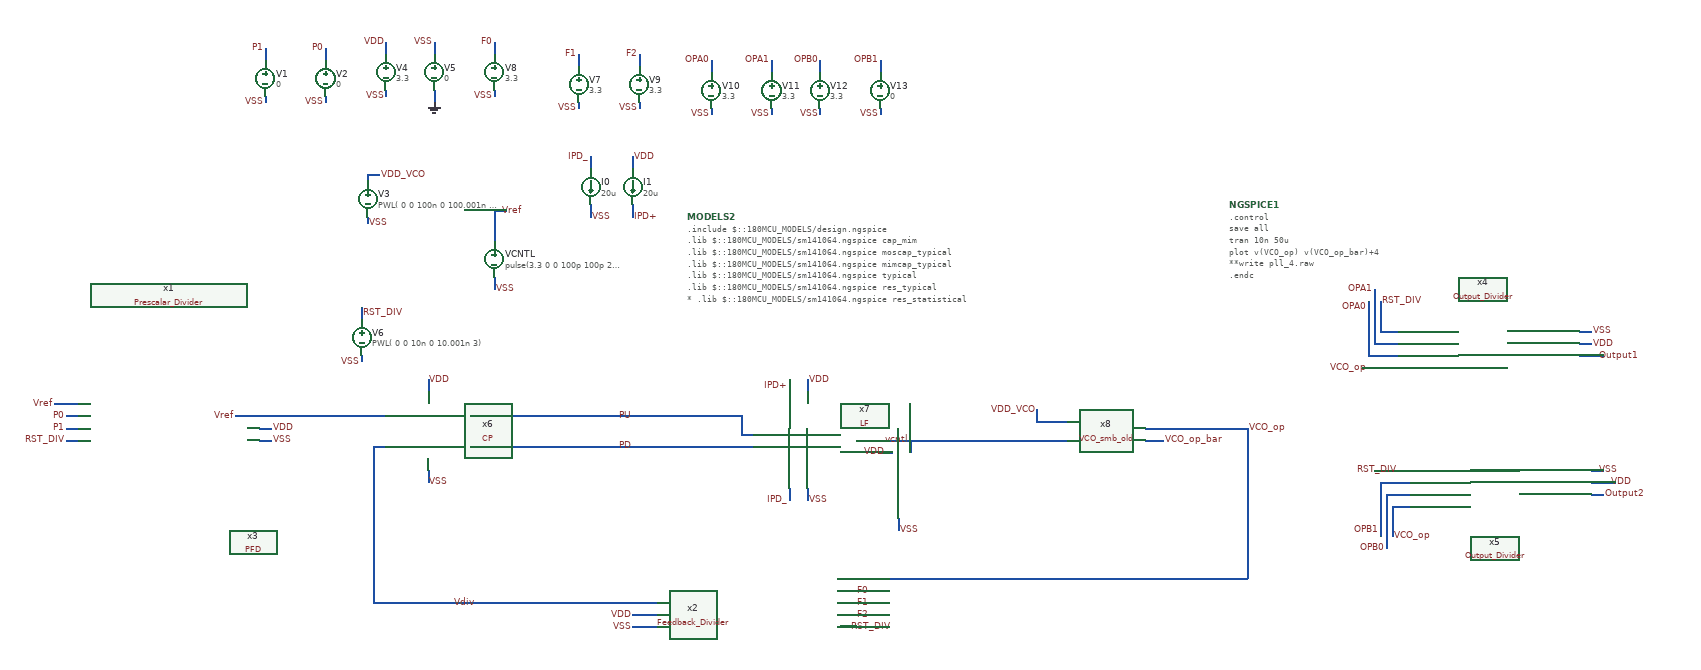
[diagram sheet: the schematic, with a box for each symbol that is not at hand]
v {xschem version=3.1.0 file_version=1.2
}
G {}
K {}
V {}
S {}
E {}
N 90 -2870 110 -2870 {
lab=P0}
N 90 -2850 110 -2850 {
lab=P1}
N 90 -2830 110 -2830 {
lab=RST_DIV}
N 410 -2830 430 -2830 {
lab=VSS}
N 410 -2850 430 -2850 {
lab=VDD}
N 420 -3400 420 -3390 {
lab=VSS}
N 420 -3480 420 -3460 {
lab=P1}
N 520 -3400 520 -3390 {
lab=VSS}
N 520 -3480 520 -3460 {
lab=P0}
N 690 -2930 690 -2910 {
lab=VDD}
N 690 -2780 690 -2760 {
lab=VSS}
N 600 -2870 620 -2870 {
lab=Vref}
N 600 -2820 620 -2820 {
lab=Vdiv}
N 760 -2820 780 -2820 {
lab=PD}
N 580 -2870 600 -2870 {
lab=Vref}
N 780 -2870 870 -2870 {
lab=PU}
N 780 -2820 870 -2820 {
lab=PD}
N 1060 -2870 1210 -2870 {
lab=PU}
N 1060 -2820 1210 -2820 {
lab=PD}
N 600 -2820 600 -2690 {
lab=Vdiv}
N 600 -2590 600 -2560 {
lab=Vdiv}
N 610 -2560 900 -2560 {
lab=Vdiv}
N 1990 -2850 2050 -2850 {
lab=VCO_op}
N 1930 -2850 1990 -2850 {
lab=VCO_op}
N 1880 -2850 1930 -2850 {
lab=VCO_op}
N 1700 -2860 1740 -2860 {
lab=VDD_VCO}
N 1880 -2830 1910 -2830 {
lab=VCO_op_bar}
N 600 -2690 600 -2590 {
lab=Vdiv}
N 600 -2560 610 -2560 {
lab=Vdiv}
N 760 -2870 780 -2870 {
lab=PU}
N 870 -2870 1060 -2870 {
lab=PU}
N 870 -2820 1060 -2820 {
lab=PD}
N 800 -3100 800 -3080 {
lab=VSS}
N 590 -3200 590 -3190 {
lab=VSS}
N 800 -3210 820 -3210 {
lab=Vref}
N 620 -3410 620 -3400 {
lab=VSS}
N 620 -3490 620 -3470 {
lab=VDD}
N 700 -3490 700 -3470 {
lab=VSS}
N 700 -3410 700 -3390 {
lab=GND}
N 1700 -2880 1700 -2860 {
lab=VDD_VCO}
N 900 -2560 1070 -2560 {
lab=Vdiv}
N 1030 -2540 1070 -2540 {
lab=VDD}
N 1030 -2520 1070 -2520 {
lab=VSS}
N 1370 -2540 1400 -2540 {
lab=F2}
N 1370 -2520 1400 -2520 {
lab=RST_DIV}
N 1400 -2600 2050 -2600 {
lab=VCO_op}
N 580 -2970 580 -2960 {
lab=VSS}
N 580 -3050 580 -3030 {
lab=RST_DIV}
N 2050 -2850 2050 -2830 {
lab=VCO_op}
N 1560 -2830 1570 -2830 {
lab=vcntl}
N 800 -3210 800 -3160 {
lab=Vref}
N 1740 -2860 1750 -2860 {
lab=VDD_VCO}
N 1570 -2830 1730 -2830 {
lab=vcntl}
N 1370 -2600 1390 -2600 {
lab=VCO_op}
N 1390 -2600 1400 -2600 {
lab=VCO_op}
N 2050 -2830 2050 -2600 {
lab=VCO_op}
N 1370 -2580 1400 -2580 {
lab=F0}
N 1370 -2560 1400 -2560 {
lab=F1}
N 590 -3270 590 -3260 {
lab=VDD_VCO}
N 590 -3270 610 -3270 {
lab=VDD_VCO}
N 940 -3390 940 -3380 {
lab=VSS}
N 940 -3470 940 -3450 {
lab=F1}
N 800 -3410 800 -3400 {
lab=VSS}
N 800 -3490 800 -3470 {
lab=F0}
N 1040 -3390 1040 -3380 {
lab=VSS}
N 1040 -3470 1040 -3450 {
lab=F2}
N 2270 -3010 2300 -3010 {
lab=RST_DIV}
N 2270 -3060 2270 -3010 {
lab=RST_DIV}
N 2240 -2950 2300 -2950 {
lab=VCO_op}
N 2260 -2990 2300 -2990 {
lab=OPA1}
N 2260 -3060 2260 -2990 {
lab=OPA1}
N 2250 -2970 2300 -2970 {
lab=OPA0}
N 2250 -3060 2250 -2970 {
lab=OPA0}
N 2600 -3010 2620 -3010 {
lab=VSS}
N 2600 -2990 2620 -2990 {
lab=VDD}
N 2600 -2970 2640 -2970 {
lab=Output1}
N 2260 -3080 2260 -3060 {
lab=OPA1}
N 2290 -2720 2320 -2720 {
lab=VCO_op}
N 2290 -2720 2290 -2670 {
lab=VCO_op}
N 2260 -2780 2320 -2780 {
lab=RST_DIV}
N 2280 -2740 2320 -2740 {
lab=OPB0}
N 2280 -2740 2280 -2670 {
lab=OPB0}
N 2270 -2760 2320 -2760 {
lab=OPB1}
N 2270 -2760 2270 -2670 {
lab=OPB1}
N 2620 -2780 2640 -2780 {
lab=VSS}
N 2620 -2740 2640 -2740 {
lab=Output2}
N 2620 -2760 2660 -2760 {
lab=VDD}
N 2280 -2670 2280 -2650 {
lab=OPB0}
N 1160 -3380 1160 -3370 {
lab=VSS}
N 1160 -3460 1160 -3440 {
lab=OPA0}
N 1260 -3380 1260 -3370 {
lab=VSS}
N 1260 -3460 1260 -3440 {
lab=OPA1}
N 1340 -3380 1340 -3370 {
lab=VSS}
N 1340 -3460 1340 -3440 {
lab=OPB0}
N 1440 -3380 1440 -3370 {
lab=VSS}
N 1440 -3460 1440 -3440 {
lab=OPB1}
N 1320 -2930 1320 -2910 {
lab=VDD}
N 1320 -2750 1320 -2730 {
lab=VSS}
N 1210 -2870 1210 -2850 {
lab=PU}
N 1210 -2850 1210 -2840 {
lab=PU}
N 1210 -2840 1230 -2840 {
lab=PU}
N 1210 -2820 1230 -2820 {
lab=PD}
N 1470 -2700 1470 -2680 {
lab=VSS}
N 1290 -2930 1290 -2910 {
lab=IPD+}
N 1290 -2750 1290 -2730 {
lab=IPD_}
N 1400 -2830 1560 -2830 {
lab=vcntl}
N 960 -3220 960 -3200 {
lab=VSS}
N 1030 -3220 1030 -3200 {
lab=IPD+}
N 960 -3300 960 -3280 {
lab=IPD_}
N 1030 -3300 1030 -3280 {
lab=VDD}
N 500 -2870 530 -2870 {
lab=Vref}
N 1490 -2830 1490 -2810 {
lab=vcntl}
N 1440 -2810 1460 -2810 {
lab=VDD}
N 1730 -2830 1750 -2830 {
lab=vcntl}
N 530 -2870 580 -2870 {
lab=Vref}
N 70 -2890 100 -2890 {
lab=Vref}
N 410 -2870 480 -2870 {
lab=Vref}
N 480 -2870 500 -2870 {
lab=Vref}
N 100 -2890 110 -2890 {
lab=Vref}
N 370 -2870 400 -2870 {
lab=Vref}
N 400 -2870 410 -2870 {
lab=Vref}
C {devices/lab_pin.sym} 90 -2850 0 0 {name=p139 sig_type=std_logic lab=P1}
C {devices/lab_pin.sym} 90 -2870 0 0 {name=p140 sig_type=std_logic lab=P0}
C {devices/lab_pin.sym} 70 -2890 0 0 {name=p141 sig_type=std_logic lab=Vref
}
C {devices/lab_pin.sym} 430 -2830 2 0 {name=p142 sig_type=std_logic lab=VSS}
C {devices/lab_pin.sym} 430 -2850 2 0 {name=p143 sig_type=std_logic lab=VDD}
C {devices/lab_pin.sym} 90 -2830 0 0 {name=p144 sig_type=std_logic lab=RST_DIV}
C {devices/vsource.sym} 420 -3430 0 0 {name=V1 value=0}
C {devices/lab_wire.sym} 420 -3390 0 0 {name=p1 sig_type=std_logic lab=VSS
}
C {devices/lab_wire.sym} 420 -3480 0 0 {name=p2 sig_type=std_logic lab=P1}
C {devices/vsource.sym} 520 -3430 0 0 {name=V2 value=0}
C {devices/lab_wire.sym} 520 -3390 0 0 {name=p3 sig_type=std_logic lab=VSS
}
C {devices/lab_wire.sym} 520 -3480 0 0 {name=p4 sig_type=std_logic lab=P0}
C {PFD.sym} 400 -2660 0 0 {name=x3}
C {devices/lab_pin.sym} 690 -2930 2 0 {name=p9 sig_type=std_logic lab=VDD}
C {devices/lab_wire.sym} 690 -2760 2 0 {name=p10 sig_type=std_logic lab=VSS}
C {devices/lab_pin.sym} 770 -2560 3 0 {name=p28 sig_type=std_logic lab=Vdiv
}
C {devices/lab_pin.sym} 2050 -2850 2 0 {name=p36 sig_type=std_logic lab=VCO_op
}
C {devices/vsource.sym} 800 -3130 0 0 {name=VCNTL value="pulse(3.3 0 0 100p 100p 250n 500n)"}
C {devices/vsource.sym} 590 -3230 0 0 {name=V3 value=" PWL( 0 0 100n 0 100.001n 3.3)"}
C {devices/code_shown.sym} 2020 -3220 0 1 {name=NGSPICE1 only_toplevel=true
value="
.control
save all
tran 10n 50u 
plot v(VCO_op) v(VCO_op_bar)+4
**write pll_4.raw
.endc
"}
C {devices/vsource.sym} 620 -3440 0 0 {name=V4 value=3.3}
C {devices/vsource.sym} 700 -3440 0 0 {name=V5 value=0}
C {devices/lab_wire.sym} 700 -3490 0 0 {name=p7 sig_type=std_logic lab=VSS}
C {devices/lab_wire.sym} 620 -3400 0 0 {name=p8 sig_type=std_logic lab=VSS
}
C {devices/lab_wire.sym} 620 -3490 0 0 {name=p11 sig_type=std_logic lab=VDD}
C {devices/gnd.sym} 700 -3390 0 0 {name=l3 lab=GND}
C {devices/lab_pin.sym} 1700 -2880 0 0 {name=p12 sig_type=std_logic lab=VDD_VCO}
C {devices/lab_pin.sym} 1910 -2830 2 0 {name=p13 sig_type=std_logic lab=VCO_op_bar
}
C {devices/lab_pin.sym} 1030 -2540 0 0 {name=p14 sig_type=std_logic lab=VDD}
C {devices/lab_wire.sym} 1030 -2520 3 0 {name=p15 sig_type=std_logic lab=VSS}
C {devices/lab_pin.sym} 610 -3270 2 0 {name=p16 sig_type=std_logic lab=VDD_VCO}
C {devices/lab_pin.sym} 810 -3210 2 0 {name=p17 sig_type=std_logic lab=Vref
}
C {devices/lab_wire.sym} 580 -2960 0 0 {name=p18 sig_type=std_logic lab=VSS
}
C {devices/vsource.sym} 580 -3000 0 0 {name=V6 value=" PWL( 0 0 10n 0 10.001n 3)"}
C {devices/lab_pin.sym} 1490 -2830 1 0 {name=p19 sig_type=std_logic lab=vcntl
}
C {devices/lab_pin.sym} 1030 -2870 1 0 {name=p20 sig_type=std_logic lab=PU}
C {devices/lab_pin.sym} 1030 -2820 1 0 {name=p21 sig_type=std_logic lab=PD}
C {Feedback_Divider.sym} 1220 -2560 2 0 {name=x2}
C {devices/lab_pin.sym} 1400 -2580 2 0 {name=p22 sig_type=std_logic lab=F0}
C {devices/lab_pin.sym} 1400 -2560 2 0 {name=p23 sig_type=std_logic lab=F1}
C {devices/lab_pin.sym} 1400 -2540 2 0 {name=p24 sig_type=std_logic lab=F2}
C {devices/vsource.sym} 940 -3420 0 0 {name=V7 value=3.3}
C {devices/lab_wire.sym} 940 -3380 0 0 {name=p26 sig_type=std_logic lab=VSS
}
C {devices/lab_wire.sym} 940 -3470 0 0 {name=p27 sig_type=std_logic lab=F1}
C {devices/vsource.sym} 800 -3440 0 0 {name=V8 value=3.3}
C {devices/lab_wire.sym} 800 -3400 0 0 {name=p25 sig_type=std_logic lab=VSS
}
C {devices/lab_wire.sym} 800 -3490 0 0 {name=p29 sig_type=std_logic lab=F0}
C {devices/vsource.sym} 1040 -3420 0 0 {name=V9 value=3.3}
C {devices/lab_wire.sym} 1040 -3380 0 0 {name=p30 sig_type=std_logic lab=VSS
}
C {devices/lab_wire.sym} 1040 -3470 0 0 {name=p31 sig_type=std_logic lab=F2}
C {devices/lab_pin.sym} 2620 -2990 2 0 {name=p32 sig_type=std_logic lab=VDD}
C {devices/lab_pin.sym} 2620 -3010 2 0 {name=p33 sig_type=std_logic lab=VSS}
C {devices/lab_wire.sym} 2250 -3050 0 0 {name=p82 sig_type=std_logic lab=OPA0}
C {devices/lab_wire.sym} 2260 -3080 0 0 {name=p83 sig_type=std_logic lab=OPA1}
C {devices/lab_pin.sym} 2270 -3060 2 0 {name=p34 sig_type=std_logic lab=RST_DIV}
C {devices/lab_pin.sym} 2630 -2970 2 0 {name=p84 sig_type=std_logic lab=Output1}
C {devices/lab_pin.sym} 2650 -2760 0 1 {name=p85 sig_type=std_logic lab=VDD}
C {devices/lab_pin.sym} 2630 -2780 0 1 {name=p86 sig_type=std_logic lab=VSS}
C {devices/lab_wire.sym} 2270 -2680 2 1 {name=p87 sig_type=std_logic lab=OPB1}
C {devices/lab_wire.sym} 2280 -2650 2 1 {name=p88 sig_type=std_logic lab=OPB0}
C {devices/lab_pin.sym} 2640 -2740 0 1 {name=p90 sig_type=std_logic lab=Output2}
C {Output_Divider.sym} 2470 -2750 0 0 {name=x5}
C {devices/lab_pin.sym} 2300 -2780 1 0 {name=p35 sig_type=std_logic lab=RST_DIV}
C {devices/lab_pin.sym} 2290 -2670 2 0 {name=p37 sig_type=std_logic lab=VCO_op
}
C {devices/lab_pin.sym} 2250 -2950 2 1 {name=p40 sig_type=std_logic lab=VCO_op
}
C {devices/vsource.sym} 1160 -3410 0 0 {name=V10 value=3.3}
C {devices/lab_wire.sym} 1160 -3370 0 0 {name=p41 sig_type=std_logic lab=VSS
}
C {devices/lab_wire.sym} 1160 -3460 0 0 {name=p42 sig_type=std_logic lab=OPA0}
C {devices/vsource.sym} 1260 -3410 0 0 {name=V11 value=3.3}
C {devices/lab_wire.sym} 1260 -3370 0 0 {name=p43 sig_type=std_logic lab=VSS
}
C {devices/lab_wire.sym} 1260 -3460 0 0 {name=p44 sig_type=std_logic lab=OPA1}
C {devices/vsource.sym} 1340 -3410 0 0 {name=V12 value=3.3}
C {devices/lab_wire.sym} 1340 -3370 0 0 {name=p45 sig_type=std_logic lab=VSS
}
C {devices/lab_wire.sym} 1340 -3460 0 0 {name=p46 sig_type=std_logic lab=OPB0
}
C {devices/vsource.sym} 1440 -3410 0 0 {name=V13 value=0}
C {devices/lab_wire.sym} 1440 -3370 0 0 {name=p47 sig_type=std_logic lab=VSS
}
C {devices/lab_wire.sym} 1440 -3460 0 0 {name=p48 sig_type=std_logic lab=OPB1}
C {devices/lab_pin.sym} 580 -3040 2 0 {name=p38 sig_type=std_logic lab=RST_DIV}
C {devices/lab_pin.sym} 1390 -2520 2 0 {name=p39 sig_type=std_logic lab=RST_DIV}
C {devices/lab_wire.sym} 1320 -2730 2 0 {name=p49 sig_type=std_logic lab=VSS}
C {devices/lab_pin.sym} 1320 -2930 2 0 {name=p50 sig_type=std_logic lab=VDD}
C {CP.sym} 740 -2630 0 0 {name=x6}
C {LF.sym} 1330 -2650 0 0 {name=x7}
C {devices/lab_wire.sym} 1470 -2680 2 0 {name=p51 sig_type=std_logic lab=VSS}
C {devices/lab_wire.sym} 1290 -2920 0 0 {name=p52 sig_type=std_logic lab=IPD+}
C {devices/lab_wire.sym} 1290 -2730 0 0 {name=p53 sig_type=std_logic lab=IPD_}
C {devices/isource.sym} 960 -3250 0 0 {name=I0 value=20u}
C {devices/isource.sym} 1030 -3250 0 0 {name=I1 value=20u}
C {devices/lab_wire.sym} 960 -3300 0 0 {name=p54 sig_type=std_logic lab=IPD_}
C {devices/lab_wire.sym} 1030 -3200 2 0 {name=p55 sig_type=std_logic lab=IPD+}
C {devices/lab_wire.sym} 960 -3200 2 0 {name=p56 sig_type=std_logic lab=VSS}
C {devices/lab_wire.sym} 1030 -3300 2 0 {name=p57 sig_type=std_logic lab=VDD}
C {Output_Divider.sym} 2450 -2980 0 0 {name=x4}
C {devices/code_shown.sym} 1120 -3200 0 0 {name=MODELS2 only_toplevel=true
format="tcleval( @value )"
value="
.include $::180MCU_MODELS/design.ngspice
.lib $::180MCU_MODELS/sm141064.ngspice cap_mim
.lib $::180MCU_MODELS/sm141064.ngspice moscap_typical
.lib $::180MCU_MODELS/sm141064.ngspice mimcap_typical
.lib $::180MCU_MODELS/sm141064.ngspice typical
.lib $::180MCU_MODELS/sm141064.ngspice res_typical
* .lib $::180MCU_MODELS/sm141064.ngspice res_statistical
"}
C {devices/lab_pin.sym} 1450 -2810 0 0 {name=p59 sig_type=std_logic lab=VDD}
C {VCO_smb_old.sym} 1900 -2840 0 0 {name=x8}
C {Prescalar_Divider.sym} 260 -2860 2 1 {name=x1}
C {devices/lab_wire.sym} 590 -3190 2 0 {name=p5 sig_type=std_logic lab=VSS
}
C {devices/lab_wire.sym} 800 -3080 2 0 {name=p6 sig_type=std_logic lab=VSS
}
C {devices/lab_pin.sym} 370 -2870 0 0 {name=p58 sig_type=std_logic lab=Vref
}
